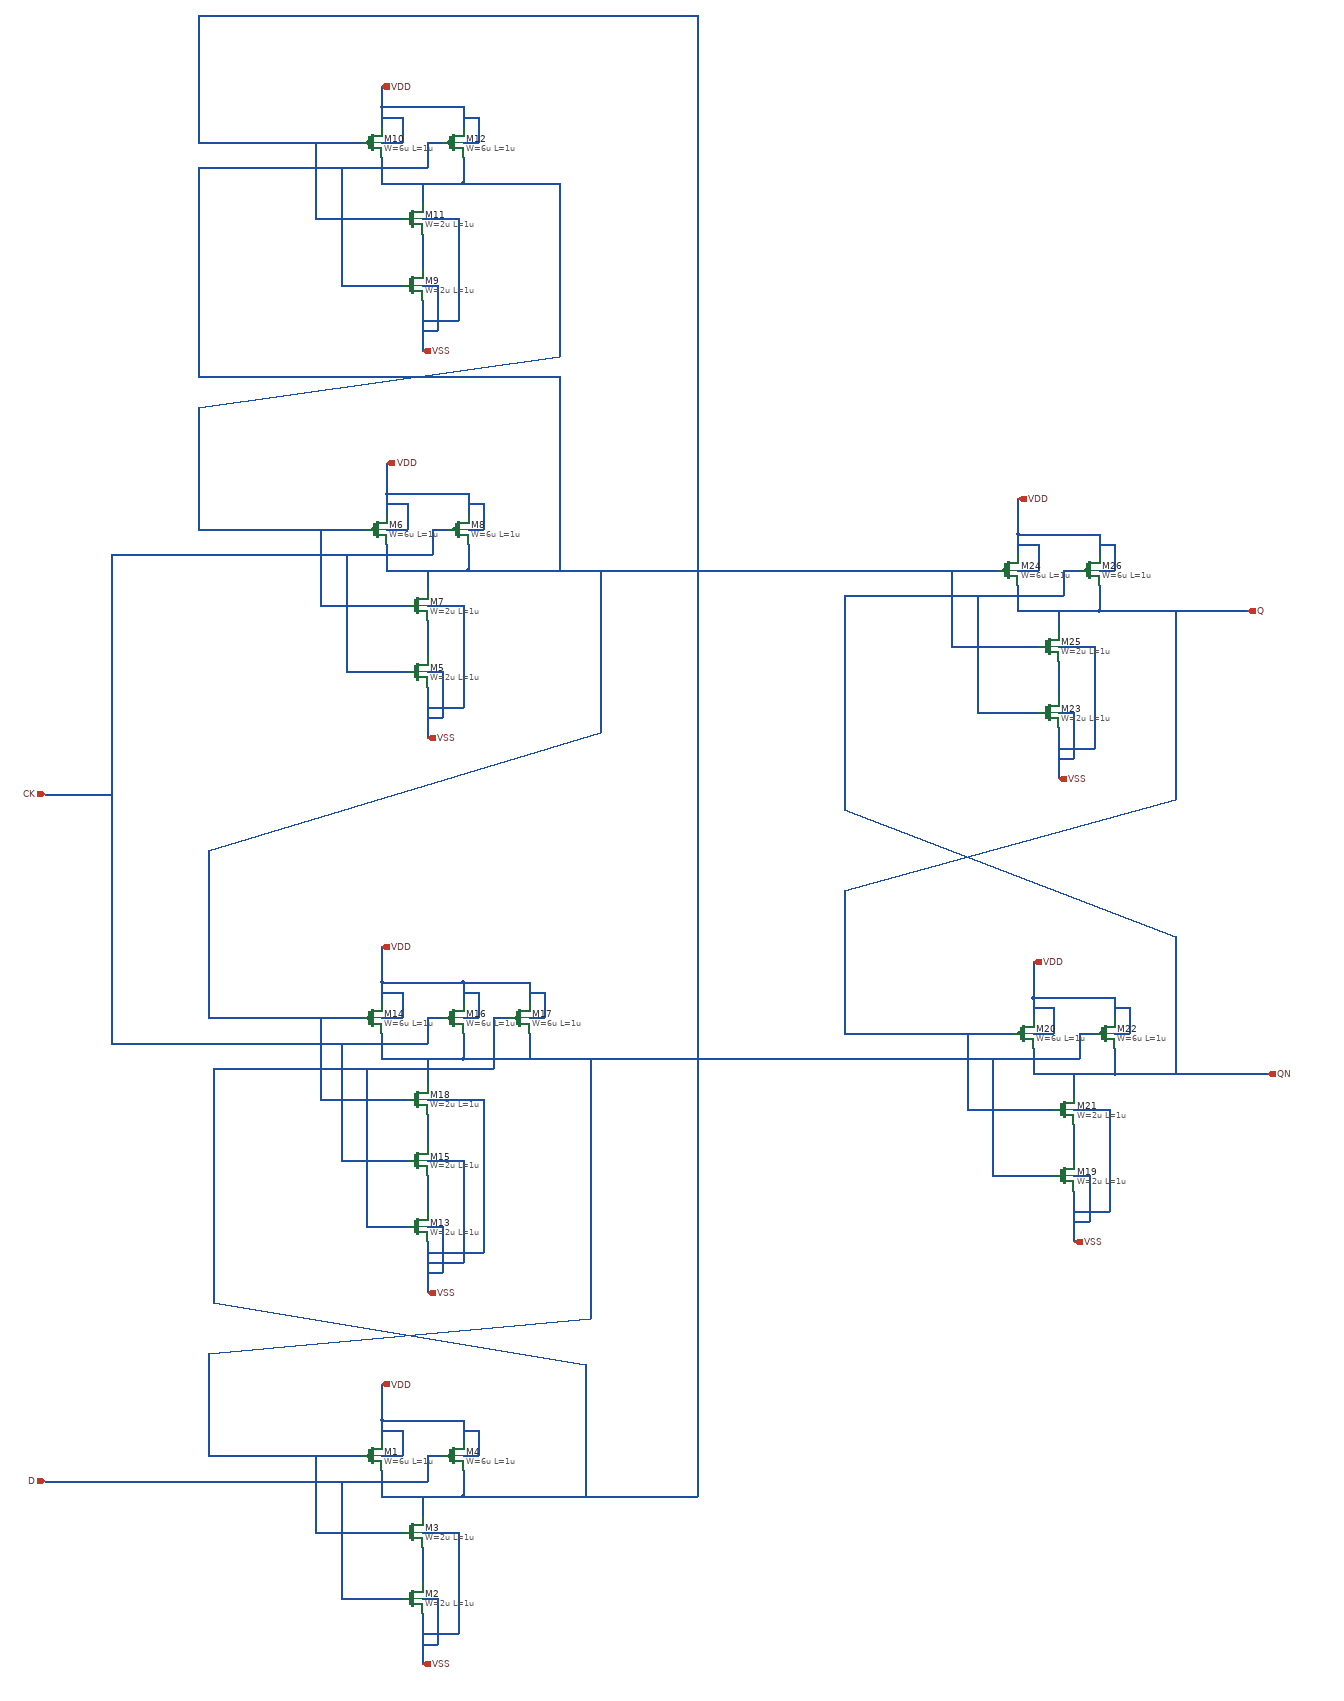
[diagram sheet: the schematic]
v {xschem version=3.4.7RC file_version=1.2}
G {}
K {}
V {}
S {}
E {}
N -10 1230 -10 1270 {lab=VDD}
N 150 1230 150 1270 {lab=VDD}
N -10 1330 -10 1380 {lab=#net1}
N -10 1380 150 1380 {lab=#net1}
N 150 1330 150 1380 {lab=#net1}
N 70 1380 70 1420 {lab=#net1}
N 70 1480 70 1550 {lab=#net2}
N 70 1610 70 1660 {lab=#net3}
N 80 1300 110 1300 {lab=D}
N 80 1300 80 1350 {lab=D}
N -180 1350 80 1350 {lab=D}
N -140 1300 -140 1450 {lab=#net4}
N -140 1450 30 1450 {lab=#net4}
N -180 1300 -50 1300 {lab=#net4}
N -90 1350 -90 1580 {lab=D}
N -90 1580 30 1580 {lab=D}
N -220 1300 -180 1300 {lab=#net4}
N -220 1350 -180 1350 {lab=D}
N 70 1660 70 1710 {lab=#net3}
N -10 1230 150 1230 {lab=VDD}
N -10 1300 30 1300 {lab=VDD}
N 30 1250 30 1300 {lab=VDD}
N -10 1250 30 1250 {lab=VDD}
N 150 1300 180 1300 {lab=VDD}
N 180 1250 180 1300 {lab=VDD}
N 150 1250 180 1250 {lab=VDD}
N 70 1450 140 1450 {lab=#net3}
N 140 1450 140 1650 {lab=#net3}
N 70 1650 140 1650 {lab=#net3}
N 70 1580 100 1580 {lab=#net3}
N 100 1580 100 1670 {lab=#net3}
N 70 1670 100 1670 {lab=#net3}
N 0 -590 0 -550 {lab=VDD}
N 160 -590 160 -550 {lab=VDD}
N 0 -490 0 -440 {lab=#net5}
N 0 -440 160 -440 {lab=#net5}
N 160 -490 160 -440 {lab=#net5}
N 80 -440 80 -400 {lab=#net5}
N 80 -340 80 -270 {lab=#net6}
N 80 -210 80 -160 {lab=VSS}
N 90 -520 120 -520 {lab=CK}
N 90 -520 90 -470 {lab=CK}
N -170 -470 90 -470 {lab=CK}
N -130 -520 -130 -370 {lab=#net7}
N -130 -370 40 -370 {lab=#net7}
N -170 -520 -40 -520 {lab=#net7}
N -80 -470 -80 -240 {lab=CK}
N -80 -240 40 -240 {lab=CK}
N -210 -520 -170 -520 {lab=#net7}
N -210 -470 -170 -470 {lab=CK}
N 80 -160 80 -110 {lab=VSS}
N 0 -590 160 -590 {lab=VDD}
N 0 -520 40 -520 {lab=VDD}
N 40 -570 40 -520 {lab=VDD}
N 0 -570 40 -570 {lab=VDD}
N 160 -520 190 -520 {lab=VDD}
N 190 -570 190 -520 {lab=VDD}
N 160 -570 190 -570 {lab=VDD}
N 80 -370 150 -370 {lab=VSS}
N 150 -370 150 -170 {lab=VSS}
N 80 -170 150 -170 {lab=VSS}
N 80 -240 110 -240 {lab=VSS}
N 110 -240 110 -150 {lab=VSS}
N 80 -150 110 -150 {lab=VSS}
N 160 -440 300 -440 {lab=#net5}
N -10 -1350 -10 -1310 {lab=VDD}
N 150 -1350 150 -1310 {lab=VDD}
N -10 -1250 -10 -1200 {lab=#net7}
N -10 -1200 150 -1200 {lab=#net7}
N 150 -1250 150 -1200 {lab=#net7}
N 70 -1200 70 -1160 {lab=#net7}
N 70 -1100 70 -1030 {lab=#net8}
N 70 -970 70 -920 {lab=VSS}
N 80 -1280 110 -1280 {lab=#net5}
N 80 -1280 80 -1230 {lab=#net5}
N -180 -1230 80 -1230 {lab=#net5}
N -140 -1280 -140 -1130 {lab=#net1}
N -140 -1130 30 -1130 {lab=#net1}
N -180 -1280 -50 -1280 {lab=#net1}
N -90 -1230 -90 -1000 {lab=#net5}
N -90 -1000 30 -1000 {lab=#net5}
N -220 -1280 -180 -1280 {lab=#net1}
N -220 -1230 -180 -1230 {lab=#net5}
N 70 -920 70 -870 {lab=VSS}
N -10 -1350 150 -1350 {lab=VDD}
N -10 -1280 30 -1280 {lab=VDD}
N 30 -1330 30 -1280 {lab=VDD}
N -10 -1330 30 -1330 {lab=VDD}
N 150 -1280 180 -1280 {lab=VDD}
N 180 -1330 180 -1280 {lab=VDD}
N 150 -1330 180 -1330 {lab=VDD}
N 70 -1130 140 -1130 {lab=VSS}
N 140 -1130 140 -930 {lab=VSS}
N 70 -930 140 -930 {lab=VSS}
N 70 -1000 100 -1000 {lab=VSS}
N 100 -1000 100 -910 {lab=VSS}
N 70 -910 100 -910 {lab=VSS}
N 150 -1200 290 -1200 {lab=#net7}
N -10 370 -10 410 {lab=VDD}
N 150 370 150 410 {lab=VDD}
N -10 470 -10 520 {lab=#net4}
N -10 520 150 520 {lab=#net4}
N 150 470 150 520 {lab=#net4}
N 80 750 80 820 {lab=#net9}
N 80 880 80 930 {lab=VSS}
N 80 440 110 440 {lab=CK}
N 80 440 80 490 {lab=CK}
N -180 490 80 490 {lab=CK}
N -180 440 -50 440 {lab=#net5}
N -90 490 -90 720 {lab=CK}
N -220 440 -180 440 {lab=#net5}
N -220 490 -180 490 {lab=CK}
N 80 930 80 980 {lab=VSS}
N -10 370 150 370 {lab=VDD}
N -10 440 30 440 {lab=VDD}
N 30 390 30 440 {lab=VDD}
N -10 390 30 390 {lab=VDD}
N 150 440 180 440 {lab=VDD}
N 180 390 180 440 {lab=VDD}
N 150 390 180 390 {lab=VDD}
N 80 720 150 720 {lab=VSS}
N 150 720 150 920 {lab=VSS}
N 80 920 150 920 {lab=VSS}
N 80 850 110 850 {lab=VSS}
N 110 850 110 940 {lab=VSS}
N 80 940 110 940 {lab=VSS}
N 150 520 290 520 {lab=#net4}
N 280 370 280 410 {lab=VDD}
N 280 470 280 520 {lab=#net4}
N 210 440 240 440 {lab=#net1}
N 210 440 210 490 {lab=#net1}
N 280 440 310 440 {lab=VDD}
N 310 390 310 440 {lab=VDD}
N 280 390 310 390 {lab=VDD}
N 150 370 280 370 {lab=VDD}
N 210 490 210 540 {lab=#net1}
N -220 540 210 540 {lab=#net1}
N 80 630 80 700 {lab=#net10}
N -130 600 40 600 {lab=#net5}
N 80 600 190 600 {lab=VSS}
N 190 600 190 900 {lab=VSS}
N 80 900 190 900 {lab=VSS}
N -130 440 -130 600 {lab=#net5}
N -90 720 40 720 {lab=CK}
N -40 540 -40 850 {lab=#net1}
N -40 850 40 850 {lab=#net1}
N 80 520 80 570 {lab=#net4}
N 1270 400 1270 440 {lab=VDD}
N 1430 400 1430 440 {lab=VDD}
N 1270 500 1270 550 {lab=QN}
N 1270 550 1430 550 {lab=QN}
N 1430 500 1430 550 {lab=QN}
N 1350 550 1350 590 {lab=QN}
N 1350 650 1350 720 {lab=#net11}
N 1350 780 1350 830 {lab=VSS}
N 1360 470 1390 470 {lab=#net4}
N 1360 470 1360 520 {lab=#net4}
N 1100 520 1360 520 {lab=#net4}
N 1140 470 1140 620 {lab=Q}
N 1140 620 1310 620 {lab=Q}
N 1100 470 1230 470 {lab=Q}
N 1190 520 1190 750 {lab=#net4}
N 1190 750 1310 750 {lab=#net4}
N 1060 470 1100 470 {lab=Q}
N 1060 520 1100 520 {lab=#net4}
N 1350 830 1350 880 {lab=VSS}
N 1270 400 1430 400 {lab=VDD}
N 1270 470 1310 470 {lab=VDD}
N 1310 420 1310 470 {lab=VDD}
N 1270 420 1310 420 {lab=VDD}
N 1430 470 1460 470 {lab=VDD}
N 1460 420 1460 470 {lab=VDD}
N 1430 420 1460 420 {lab=VDD}
N 1350 620 1420 620 {lab=VSS}
N 1420 620 1420 820 {lab=VSS}
N 1350 820 1420 820 {lab=VSS}
N 1350 750 1380 750 {lab=VSS}
N 1380 750 1380 840 {lab=VSS}
N 1350 840 1380 840 {lab=VSS}
N 1430 550 1570 550 {lab=QN}
N 1240 -510 1240 -470 {lab=VDD}
N 1400 -510 1400 -470 {lab=VDD}
N 1240 -410 1240 -360 {lab=Q}
N 1240 -360 1400 -360 {lab=Q}
N 1400 -410 1400 -360 {lab=Q}
N 1320 -360 1320 -320 {lab=Q}
N 1320 -260 1320 -190 {lab=#net12}
N 1320 -130 1320 -80 {lab=VSS}
N 1330 -440 1360 -440 {lab=QN}
N 1330 -440 1330 -390 {lab=QN}
N 1070 -390 1330 -390 {lab=QN}
N 1110 -440 1110 -290 {lab=#net5}
N 1110 -290 1280 -290 {lab=#net5}
N 1070 -440 1200 -440 {lab=#net5}
N 1160 -390 1160 -160 {lab=QN}
N 1160 -160 1280 -160 {lab=QN}
N 1030 -440 1070 -440 {lab=#net5}
N 1030 -390 1070 -390 {lab=QN}
N 1320 -80 1320 -30 {lab=VSS}
N 1240 -510 1400 -510 {lab=VDD}
N 1240 -440 1280 -440 {lab=VDD}
N 1280 -490 1280 -440 {lab=VDD}
N 1240 -490 1280 -490 {lab=VDD}
N 1400 -440 1430 -440 {lab=VDD}
N 1430 -490 1430 -440 {lab=VDD}
N 1400 -490 1430 -490 {lab=VDD}
N 1320 -290 1390 -290 {lab=VSS}
N 1390 -290 1390 -90 {lab=VSS}
N 1320 -90 1390 -90 {lab=VSS}
N 1320 -160 1350 -160 {lab=VSS}
N 1350 -160 1350 -70 {lab=VSS}
N 1320 -70 1350 -70 {lab=VSS}
N 1400 -360 1540 -360 {lab=Q}
N 1540 -360 1650 -360 {lab=Q}
N 900 -390 1040 -390 {lab=QN}
N 900 -390 900 30 {lab=QN}
N 900 30 1550 280 {lab=QN}
N 1550 280 1550 550 {lab=QN}
N 900 470 1060 470 {lab=Q}
N 900 190 900 470 {lab=Q}
N 900 190 1550 10 {lab=Q}
N 1550 -360 1550 10 {lab=Q}
N 290 520 1060 520 {lab=#net4}
N 280 1380 610 1380 {lab=#net1}
N 610 -1530 610 1380 {lab=#net1}
N -370 -1530 610 -1530 {lab=#net1}
N -370 -1530 -370 -1290 {lab=#net1}
N -370 -1280 -220 -1280 {lab=#net1}
N -370 -1290 -370 -1280 {lab=#net1}
N 300 -440 1040 -440 {lab=#net5}
N -370 -1230 -220 -1230 {lab=#net5}
N -370 -1230 -370 -820 {lab=#net5}
N -370 -820 340 -820 {lab=#net5}
N 340 -820 340 -440 {lab=#net5}
N -360 -520 -210 -520 {lab=#net7}
N -370 -520 -360 -520 {lab=#net7}
N -370 -760 -370 -520 {lab=#net7}
N -370 -760 340 -860 {lab=#net7}
N 340 -1200 340 -860 {lab=#net7}
N 290 -1200 340 -1200 {lab=#net7}
N -540 -470 -540 490 {lab=CK}
N -540 -470 -210 -470 {lab=CK}
N -540 490 -220 490 {lab=CK}
N 420 -440 420 -120 {lab=#net5}
N -350 110 420 -120 {lab=#net5}
N -350 110 -350 440 {lab=#net5}
N -350 440 -220 440 {lab=#net5}
N -350 1300 -220 1300 {lab=#net4}
N -350 1100 -350 1300 {lab=#net4}
N -350 1100 400 1030 {lab=#net4}
N 400 530 400 1030 {lab=#net4}
N 400 520 400 530 {lab=#net4}
N -340 540 -220 540 {lab=#net1}
N -340 540 -340 1000 {lab=#net1}
N -340 1000 390 1120 {lab=#net1}
N 390 1120 390 1370 {lab=#net1}
N 390 1370 390 1380 {lab=#net1}
N 150 1380 280 1380 {lab=#net1}
N -670 1350 -220 1350 {lab=D}
N -670 0 -540 0 {lab=CK}
N -10 -1390 -10 -1350 {lab=VDD}
N 1570 550 1730 550 {lab=QN}
N 1650 -360 1690 -360 {lab=Q}
N 0 -650 0 -590 {lab=VDD}
N 1240 -580 1240 -510 {lab=VDD}
N 1270 330 1270 400 {lab=VDD}
N -10 300 -10 370 {lab=VDD}
N -10 1160 -10 1230 {lab=VDD}
C {primitives/nfet.sym} 50 1580 0 0 {name=M2
model=nmos
W=2u
L=1u
m=1
}
C {primitives/pfet.sym} -30 1300 0 0 {name=M1 
model=pmos
W=6u
L=1u
m=1
}
C {primitives/nfet.sym} 50 1450 0 0 {name=M3
model=nmos
W=2u
L=1u
m=1
}
C {primitives/pfet.sym} 130 1300 0 0 {name=M4 
model=pmos
W=6u
L=1u
m=1
}
C {primitives/nfet.sym} 60 -240 0 0 {name=M5
model=nmos
W=2u
L=1u
m=1
}
C {primitives/pfet.sym} -20 -520 0 0 {name=M6 
model=pmos
W=6u
L=1u
m=1
}
C {primitives/nfet.sym} 60 -370 0 0 {name=M7
model=nmos
W=2u
L=1u
m=1
}
C {primitives/pfet.sym} 140 -520 0 0 {name=M8 
model=pmos
W=6u
L=1u
m=1
}
C {primitives/nfet.sym} 50 -1000 0 0 {name=M9
model=nmos
W=2u
L=1u
m=1
}
C {primitives/pfet.sym} -30 -1280 0 0 {name=M10 
model=pmos
W=6u
L=1u
m=1
}
C {primitives/nfet.sym} 50 -1130 0 0 {name=M11
model=nmos
W=2u
L=1u
m=1
}
C {primitives/pfet.sym} 130 -1280 0 0 {name=M12 
model=pmos
W=6u
L=1u
m=1
}
C {primitives/nfet.sym} 60 850 0 0 {name=M13
model=nmos
W=2u
L=1u
m=1
}
C {primitives/pfet.sym} -30 440 0 0 {name=M14 
model=pmos
W=6u
L=1u
m=1
}
C {primitives/nfet.sym} 60 720 0 0 {name=M15
model=nmos
W=2u
L=1u
m=1
}
C {primitives/pfet.sym} 130 440 0 0 {name=M16 
model=pmos
W=6u
L=1u
m=1
}
C {primitives/pfet.sym} 260 440 0 0 {name=M17 
model=pmos
W=6u
L=1u
m=1
}
C {primitives/nfet.sym} 60 600 0 0 {name=M18
model=nmos
W=2u
L=1u
m=1
}
C {primitives/nfet.sym} 1330 750 0 0 {name=M19
model=nmos
W=2u
L=1u
m=1
}
C {primitives/pfet.sym} 1250 470 0 0 {name=M20 
model=pmos
W=6u
L=1u
m=1
}
C {primitives/nfet.sym} 1330 620 0 0 {name=M21
model=nmos
W=2u
L=1u
m=1
}
C {primitives/pfet.sym} 1410 470 0 0 {name=M22 
model=pmos
W=6u
L=1u
m=1
}
C {primitives/nfet.sym} 1300 -160 0 0 {name=M23
model=nmos
W=2u
L=1u
m=1
}
C {primitives/pfet.sym} 1220 -440 0 0 {name=M24 
model=pmos
W=6u
L=1u
m=1
}
C {primitives/nfet.sym} 1300 -290 0 0 {name=M25
model=nmos
W=2u
L=1u
m=1
}
C {primitives/pfet.sym} 1380 -440 0 0 {name=M26 
model=pmos
W=6u
L=1u
m=1
}
C {devices/iopin.sym} 0 -650 0 1 {name=p3 lab=VDD}
C {devices/iopin.sym} -10 -1390 0 1 {name=p4 lab=VDD}
C {devices/ipin.sym} -670 0 0 0 {name=p6 lab=CK}
C {devices/ipin.sym} -670 1350 0 0 {name=p7 lab=D}
C {devices/opin.sym} 1690 -360 0 0 {name=p8 lab=Q}
C {devices/iopin.sym} 70 -870 0 1 {name=p9 lab=VSS}
C {devices/opin.sym} 1730 550 0 0 {name=p1 lab=QN}
C {devices/iopin.sym} -10 300 0 1 {name=p2 lab=VDD}
C {devices/iopin.sym} 1240 -580 0 1 {name=p5 lab=VDD}
C {devices/iopin.sym} 1270 330 0 1 {name=p10 lab=VDD}
C {devices/iopin.sym} -10 1160 0 1 {name=p11 lab=VDD}
C {devices/iopin.sym} 80 -110 0 1 {name=p12 lab=VSS}
C {devices/iopin.sym} 1320 -30 0 1 {name=p13 lab=VSS}
C {devices/iopin.sym} 1350 880 0 1 {name=p14 lab=VSS}
C {devices/iopin.sym} 80 980 0 1 {name=p15 lab=VSS}
C {devices/iopin.sym} 70 1710 0 1 {name=p16 lab=VSS}
